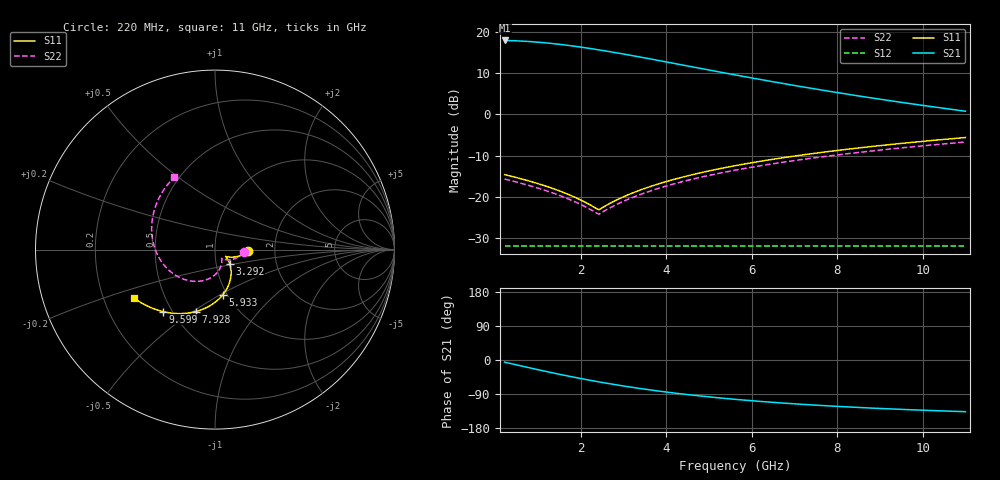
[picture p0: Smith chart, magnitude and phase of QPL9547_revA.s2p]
! written by passband
# GHZ S MA R 50
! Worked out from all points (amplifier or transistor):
!   201 points, 220 MHz to 11 GHz, reference 50 ohm
!   highest |S21| = 18.0 dB at 220 MHz (marker M1)
!   |S21| within 3 dB of that: start of sweep to 2.838 GHz
!   unconditionally stable (mu >= 1): start of sweep to end of sweep
!   at 1.999 GHz: K = 3.06, MAG = 16.4 dB, |S12| = -32.0 dB
!   at 5.61 GHz: K = 5.99, MAG = 10.1 dB, |S12| = -32.0 dB
!   at 11 GHz: K = 10.59, MAG = 3.1 dB, |S12| = -32.0 dB
!   S11 on the Smith chart (normalised r, x): 220 MHz: 1.46, -0.03; 3.292 GHz: 1.16, -0.19; 5.933 GHz: 0.95, -0.51; 7.928 GHz: 0.65, -0.51; 9.599 GHz: 0.45, -0.39; 11 GHz: 0.33, -0.25
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0.22  0.1859 -3.0  7.923 -5.7  0.02512 -8.2  0.164 -4.8
0.4356  0.1745 -5.9  7.866 -11.3  0.02512 -16.3  0.1539 -9.5
0.6512  0.163 -8.8  7.773 -16.8  0.02512 -24.3  0.1438 -14.2
0.9207  0.1487 -12.5  7.61 -23.6  0.02512 -34.4  0.1312 -20.1
1.1902  0.1344 -16.1  7.402 -30.3  0.02512 -44.5  0.1186 -26.0
1.6214  0.1115 -21.9  6.994 -40.5  0.02512 -60.6  0.0984 -35.5
2.0526  0.08866 -27.8  6.524 -50.0  0.02512 -76.7  0.07821 -44.9
2.4299  0.06969 -32.9  6.087 -57.8  0.02512 -90.8  0.06148 -53.2
2.6455  0.08113 -35.8  5.834 -62.0  0.02512 -98.8  0.07157 -57.9
3.2923  0.1155 -44.5  5.092 -73.6  0.02512 -123.0  0.1019 -72.0
3.8313  0.1441 -51.8  4.518 -82.1  0.02512 -143.1  0.1271 -83.8
4.2086  0.1641 -56.9  4.148 -87.5  0.02512 -157.2  0.1448 -92.1
4.6398  0.187 -62.7  3.761 -93.0  0.02512 -173.3  0.1649 -101.5
5.1249  0.2127 -69.3  3.371 -98.7  0.02512 168.6  0.1877 -112.1
5.61  0.2385 -75.9  3.025 -103.8  0.02512 150.5  0.2104 -122.8
5.9334  0.2556 -80.2  2.818 -106.9  0.02512 138.4  0.2255 -129.8
6.688  0.2957 -90.4  2.399 -113.3  0.02512 110.2  0.2608 -146.3
7.4426  0.3357 -100.7  2.057 -118.8  0.02512 82.0  0.2962 -162.9
7.9277  0.3615 -107.2  1.871 -121.9  0.02512 63.9  0.3189 -173.5
9.2213  0.4301 -124.7  1.473 -129.0  0.02512 15.6  0.3795 158.2
9.5986  0.4502 -129.8  1.379 -130.7  0.02512 1.5  0.3971 150.0
11  0.5245 -148.8  1.096 -136.4  0.02512 -50.8  0.4627 119.3
